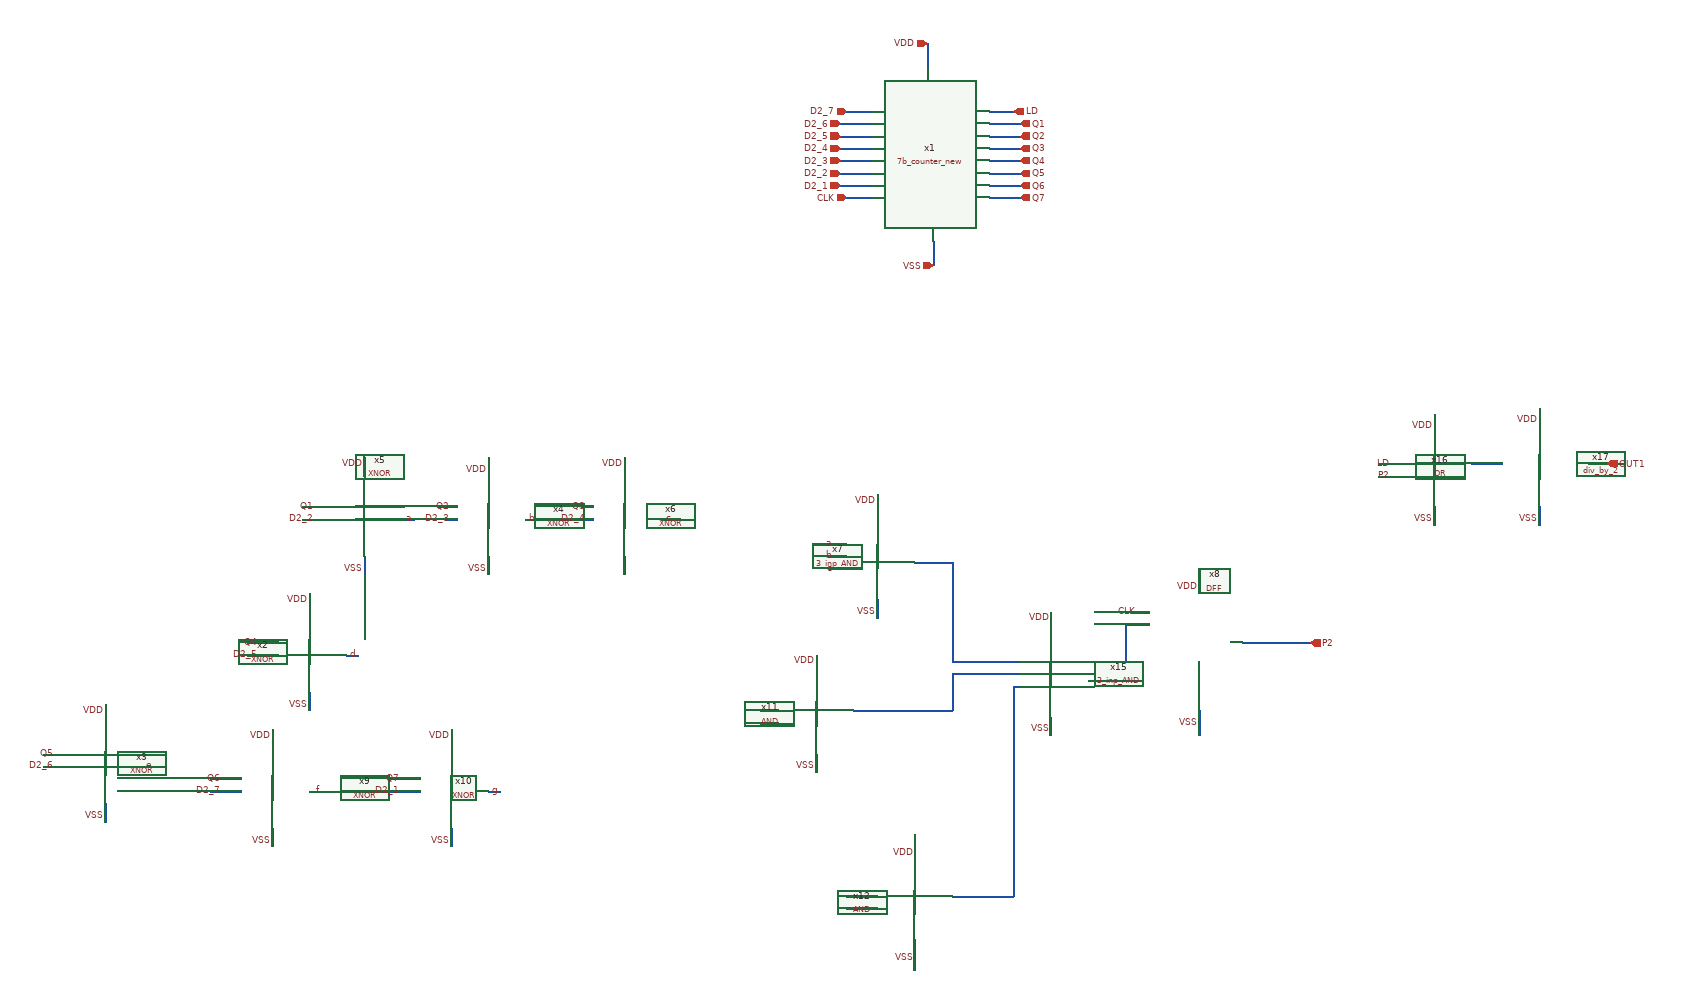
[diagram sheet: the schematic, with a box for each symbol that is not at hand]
v {xschem version=3.1.0 file_version=1.2
}
G {}
K {}
V {}
S {}
E {}
N -880 -2260 -880 -2220 {
lab=VDD}
N -870 -1940 -870 -1900 {
lab=VSS}
N -1010 -2010 -970 -2010 {
lab=CLK}
N -780 -2150 -740 -2150 {
lab=LD}
N -1020 -2030 -970 -2030 {
lab=D2_1}
N -1020 -2070 -970 -2070 {
lab=D2_3}
N -1020 -2050 -970 -2050 {
lab=D2_2}
N -1020 -2090 -970 -2090 {
lab=D2_4}
N -1020 -2110 -970 -2110 {
lab=D2_5}
N -1020 -2130 -970 -2130 {
lab=D2_6}
N -1010 -2150 -970 -2150 {
lab=D2_7}
N -780 -2130 -730 -2130 {
lab=Q1}
N -780 -2110 -730 -2110 {
lab=Q2}
N -780 -2090 -730 -2090 {
lab=Q3}
N -780 -2070 -730 -2070 {
lab=Q4}
N -780 -2050 -730 -2050 {
lab=Q5}
N -780 -2030 -730 -2030 {
lab=Q6}
N -780 -2010 -730 -2010 {
lab=Q7}
N -1890 -1510 -1840 -1510 {
lab=Q1}
N -1890 -1490 -1840 -1490 {
lab=D2_2}
N -1670 -1510 -1640 -1510 {
lab=Q2}
N -1660 -1490 -1640 -1490 {
lab=D2_3}
N -1440 -1510 -1420 -1510 {
lab=Q3}
N -1440 -1490 -1420 -1490 {
lab=D2_4}
N -1530 -1490 -1500 -1490 {
lab=b}
N -1790 -1590 -1790 -1560 {
lab=VDD}
N -1790 -1430 -1790 -1400 {
lab=VSS}
N -1590 -1590 -1590 -1560 {
lab=VDD}
N -1590 -1430 -1590 -1400 {
lab=VSS}
N -1370 -1590 -1370 -1560 {
lab=VDD}
N -1370 -1430 -1370 -1400 {
lab=#net1}
N -1310 -1490 -1280 -1490 {
lab=c}
N -1730 -1490 -1710 -1490 {
lab=a}
N -1040 -1450 -1010 -1450 {
lab=a}
N -1040 -1430 -1010 -1430 {
lab=b}
N -1040 -1410 -1010 -1410 {
lab=c}
N -960 -1530 -960 -1500 {
lab=VDD}
N -370 -1290 -330 -1290 {
lab=P2}
N -330 -1290 -260 -1290 {
lab=P2}
N -440 -1410 -440 -1370 {
lab=VDD}
N -440 -1180 -440 -1140 {
lab=VSS}
N -550 -1340 -520 -1340 {
lab=CLK}
N -1980 -1290 -1930 -1290 {
lab=Q4}
N -1980 -1270 -1930 -1270 {
lab=D2_5}
N -1880 -1370 -1880 -1340 {
lab=VDD}
N -1880 -1210 -1880 -1180 {
lab=VSS}
N -1820 -1270 -1800 -1270 {
lab=d}
N -2310 -1110 -2260 -1110 {
lab=Q5}
N -2310 -1090 -2260 -1090 {
lab=D2_6}
N -2210 -1190 -2210 -1160 {
lab=VDD}
N -2210 -1030 -2210 -1000 {
lab=VSS}
N -2150 -1090 -2130 -1090 {
lab=e}
N -2040 -1070 -1990 -1070 {
lab=Q6}
N -2040 -1050 -1990 -1050 {
lab=D2_7}
N -1940 -1150 -1940 -1120 {
lab=VDD}
N -1940 -990 -1940 -960 {
lab=VSS}
N -1880 -1050 -1860 -1050 {
lab=f}
N -1750 -1070 -1700 -1070 {
lab=Q7}
N -1750 -1050 -1700 -1050 {
lab=D2_1}
N -1650 -1150 -1650 -1120 {
lab=VDD}
N -1650 -990 -1650 -960 {
lab=VSS}
N -1590 -1050 -1570 -1050 {
lab=g}
N -960 -1360 -960 -1330 {
lab=VSS}
N -1150 -1180 -1120 -1180 {
lab=d}
N -1150 -1160 -1120 -1160 {
lab=e}
N -1060 -1270 -1060 -1240 {
lab=VDD}
N -1060 -1110 -1060 -1080 {
lab=VSS}
N -900 -980 -900 -940 {
lab=VDD}
N -900 -810 -900 -760 {
lab=VSS}
N -1010 -880 -960 -880 {
lab=g}
N -1010 -860 -960 -860 {
lab=f}
N -760 -1260 -730 -1260 {
lab=#net2}
N -760 -1240 -730 -1240 {
lab=#net3}
N -680 -1340 -680 -1310 {
lab=VDD}
N -680 -1170 -680 -1140 {
lab=VSS}
N -900 -1420 -840 -1420 {
lab=#net2}
N -840 -1420 -840 -1260 {
lab=#net2}
N -840 -1260 -760 -1260 {
lab=#net2}
N -910 -1180 -840 -1180 {
lab=#net3}
N -840 -1240 -840 -1180 {
lab=#net3}
N -840 -1240 -760 -1240 {
lab=#net3}
N -740 -1220 -730 -1220 {
lab=#net4}
N -560 -1320 -520 -1320 {
lab=#net5}
N -560 -1320 -560 -1230 {
lab=#net5}
N -620 -1230 -560 -1230 {
lab=#net5}
N -150 -1580 -110 -1580 {
lab=LD}
N -150 -1560 -110 -1560 {
lab=P2}
N -60 -1660 -60 -1630 {
lab=VDD}
N -60 -1510 -60 -1480 {
lab=VSS}
N 0 -1580 50 -1580 {
lab=#net6}
N 110 -1670 110 -1640 {
lab=VDD}
N 110 -1510 110 -1480 {
lab=VSS}
N 190 -1580 230 -1580 {
lab=OUT1}
N -740 -1220 -740 -880 {
lab=#net4}
N -1000 -1180 -910 -1180 {
lab=#net3}
N -840 -880 -740 -880 {
lab=#net4}
C {devices/iopin.sym} -880 -2260 3 0 {name=p1 lab=VDD}
C {devices/iopin.sym} -870 -1900 1 0 {name=p2 lab=VSS}
C {devices/ipin.sym} -1020 -2030 0 0 {name=p3 lab=D2_1}
C {devices/ipin.sym} -1010 -2010 0 0 {name=p4 lab=CLK}
C {devices/ipin.sym} -1020 -2050 0 0 {name=p5 lab=D2_2}
C {devices/ipin.sym} -1020 -2070 0 0 {name=p6 lab=D2_3}
C {devices/ipin.sym} -1020 -2090 0 0 {name=p7 lab=D2_4}
C {devices/ipin.sym} -1020 -2110 0 0 {name=p8 lab=D2_5}
C {devices/ipin.sym} -1020 -2130 0 0 {name=p9 lab=D2_6}
C {devices/ipin.sym} -1010 -2150 0 0 {name=p10 lab=D2_7}
C {devices/opin.sym} -740 -2150 0 0 {name=p12 lab=LD}
C {devices/opin.sym} -730 -2130 0 0 {name=p13 lab=Q1}
C {devices/opin.sym} -730 -2110 0 0 {name=p14 lab=Q2}
C {devices/opin.sym} -730 -2090 0 0 {name=p15 lab=Q3}
C {devices/opin.sym} -730 -2070 0 0 {name=p16 lab=Q4}
C {devices/opin.sym} -730 -2050 0 0 {name=p17 lab=Q5}
C {devices/opin.sym} -730 -2030 0 0 {name=p18 lab=Q6}
C {devices/opin.sym} -730 -2010 0 0 {name=p19 lab=Q7}
C {XNOR.sym} -1490 -1490 0 0 {name=x4}
C {XNOR.sym} -1690 -1490 0 0 {name=x5}
C {XNOR.sym} -1270 -1490 0 0 {name=x6}
C {devices/lab_wire.sym} -1790 -1580 0 0 {name=p21 sig_type=std_logic lab=VDD}
C {devices/lab_wire.sym} -1590 -1570 0 0 {name=p22 sig_type=std_logic lab=VDD}
C {devices/lab_wire.sym} -1370 -1580 0 0 {name=p23 sig_type=std_logic lab=VDD}
C {devices/lab_wire.sym} -1790 -1410 0 0 {name=p24 sig_type=std_logic lab=VSS}
C {devices/lab_wire.sym} -1590 -1410 0 0 {name=p25 sig_type=std_logic lab=VSS}
C {devices/lab_wire.sym} -960 -1340 0 0 {name=p26 sig_type=std_logic lab=VSS}
C {devices/lab_wire.sym} -1870 -1510 0 0 {name=p27 sig_type=std_logic lab=Q1}
C {devices/lab_wire.sym} -1650 -1510 0 0 {name=p28 sig_type=std_logic lab=Q2}
C {devices/lab_wire.sym} -1430 -1510 0 0 {name=p29 sig_type=std_logic lab=Q3}
C {devices/lab_wire.sym} -1430 -1490 0 0 {name=p30 sig_type=std_logic lab=D2_4}
C {devices/lab_wire.sym} -1650 -1490 0 0 {name=p31 sig_type=std_logic lab=D2_3}
C {devices/lab_wire.sym} -1870 -1490 0 0 {name=p32 sig_type=std_logic lab=D2_2}
C {3_inp_AND.sym} -860 -1430 0 0 {name=x7}
C {devices/lab_wire.sym} -960 -1520 0 0 {name=p33 sig_type=std_logic lab=VDD}
C {devices/lab_wire.sym} -1710 -1490 0 0 {name=p35 sig_type=std_logic lab=a}
C {devices/lab_wire.sym} -1510 -1490 0 0 {name=p36 sig_type=std_logic lab=b}
C {devices/lab_wire.sym} -1290 -1490 0 0 {name=p37 sig_type=std_logic lab=c}
C {devices/lab_wire.sym} -1030 -1450 0 0 {name=p38 sig_type=std_logic lab=a}
C {devices/opin.sym} -260 -1290 0 0 {name=p43 lab=P2}
C {devices/lab_wire.sym} -440 -1380 0 0 {name=p41 sig_type=std_logic lab=VDD}
C {devices/lab_wire.sym} -440 -1160 0 0 {name=p42 sig_type=std_logic lab=VSS}
C {devices/lab_wire.sym} -540 -1340 0 0 {name=p44 sig_type=std_logic lab=CLK}
C {DFF.sym} -370 -1320 0 0 {name=x8}
C {XNOR.sym} -1780 -1270 0 0 {name=x2}
C {devices/lab_wire.sym} -1880 -1360 0 0 {name=p45 sig_type=std_logic lab=VDD}
C {devices/lab_wire.sym} -1880 -1190 0 0 {name=p46 sig_type=std_logic lab=VSS}
C {devices/lab_wire.sym} -1960 -1290 0 0 {name=p47 sig_type=std_logic lab=Q4}
C {devices/lab_wire.sym} -1960 -1270 0 0 {name=p48 sig_type=std_logic lab=D2_5}
C {devices/lab_wire.sym} -1800 -1270 0 0 {name=p49 sig_type=std_logic lab=d}
C {XNOR.sym} -2110 -1090 0 0 {name=x3}
C {devices/lab_wire.sym} -2210 -1180 0 0 {name=p50 sig_type=std_logic lab=VDD}
C {devices/lab_wire.sym} -2210 -1010 0 0 {name=p51 sig_type=std_logic lab=VSS}
C {devices/lab_wire.sym} -2290 -1110 0 0 {name=p52 sig_type=std_logic lab=Q5}
C {devices/lab_wire.sym} -2290 -1090 0 0 {name=p53 sig_type=std_logic lab=D2_6}
C {devices/lab_wire.sym} -2130 -1090 0 0 {name=p54 sig_type=std_logic lab=e}
C {XNOR.sym} -1840 -1050 0 0 {name=x9}
C {devices/lab_wire.sym} -1940 -1140 0 0 {name=p55 sig_type=std_logic lab=VDD}
C {devices/lab_wire.sym} -1940 -970 0 0 {name=p56 sig_type=std_logic lab=VSS}
C {devices/lab_wire.sym} -2020 -1070 0 0 {name=p57 sig_type=std_logic lab=Q6}
C {devices/lab_wire.sym} -2020 -1050 0 0 {name=p58 sig_type=std_logic lab=D2_7}
C {devices/lab_wire.sym} -1860 -1050 0 0 {name=p59 sig_type=std_logic lab=f}
C {XNOR.sym} -1550 -1050 0 0 {name=x10}
C {devices/lab_wire.sym} -1650 -1140 0 0 {name=p60 sig_type=std_logic lab=VDD}
C {devices/lab_wire.sym} -1650 -970 0 0 {name=p61 sig_type=std_logic lab=VSS}
C {devices/lab_wire.sym} -1730 -1070 0 0 {name=p62 sig_type=std_logic lab=Q7}
C {devices/lab_wire.sym} -1570 -1050 0 0 {name=p64 sig_type=std_logic lab=g}
C {devices/lab_wire.sym} -1060 -1090 0 0 {name=p34 sig_type=std_logic lab=VSS}
C {devices/lab_wire.sym} -1060 -1260 0 0 {name=p70 sig_type=std_logic lab=VDD}
C {devices/lab_wire.sym} -1140 -1180 0 0 {name=p71 sig_type=std_logic lab=d}
C {devices/lab_wire.sym} -1140 -1160 0 0 {name=p72 sig_type=std_logic lab=e}
C {devices/lab_wire.sym} -990 -860 0 0 {name=p75 sig_type=std_logic lab=f}
C {devices/lab_wire.sym} -900 -950 0 0 {name=p76 sig_type=std_logic lab=VDD}
C {devices/lab_wire.sym} -900 -780 0 0 {name=p77 sig_type=std_logic lab=VSS}
C {devices/lab_wire.sym} -680 -1150 0 0 {name=p80 sig_type=std_logic lab=VSS}
C {3_inp_AND.sym} -580 -1240 0 0 {name=x15}
C {devices/lab_wire.sym} -680 -1330 0 0 {name=p81 sig_type=std_logic lab=VDD}
C {OR.sym} 40 -1560 0 0 {name=x16}
C {devices/lab_wire.sym} -130 -1580 0 0 {name=p82 sig_type=std_logic lab=LD}
C {devices/lab_wire.sym} -130 -1560 0 0 {name=p83 sig_type=std_logic lab=P2}
C {devices/lab_wire.sym} -60 -1640 0 0 {name=p84 sig_type=std_logic lab=VDD}
C {devices/lab_wire.sym} -60 -1490 0 0 {name=p85 sig_type=std_logic lab=VSS}
C {div_by_2.sym} 200 -1560 0 0 {name=x17}
C {devices/lab_wire.sym} 110 -1650 0 0 {name=p86 sig_type=std_logic lab=VDD}
C {devices/lab_wire.sym} 110 -1490 0 0 {name=p87 sig_type=std_logic lab=VSS}
C {devices/opin.sym} 220 -1580 0 0 {name=p88 lab=OUT1}
C {devices/lab_wire.sym} -1030 -1430 0 0 {name=p94 sig_type=std_logic lab=b}
C {devices/lab_wire.sym} -1030 -1410 0 0 {name=p95 sig_type=std_logic lab=c}
C {devices/lab_wire.sym} -990 -880 0 0 {name=p39 sig_type=std_logic lab=g}
C {7b_counter_new.sym} -820 -2060 0 0 {name=x1}
C {devices/lab_wire.sym} -1730 -1050 0 0 {name=p11 sig_type=std_logic lab=D2_1}
C {AND.sym} -970 -1160 0 0 {name=x11}
C {AND.sym} -810 -860 0 0 {name=x12}
